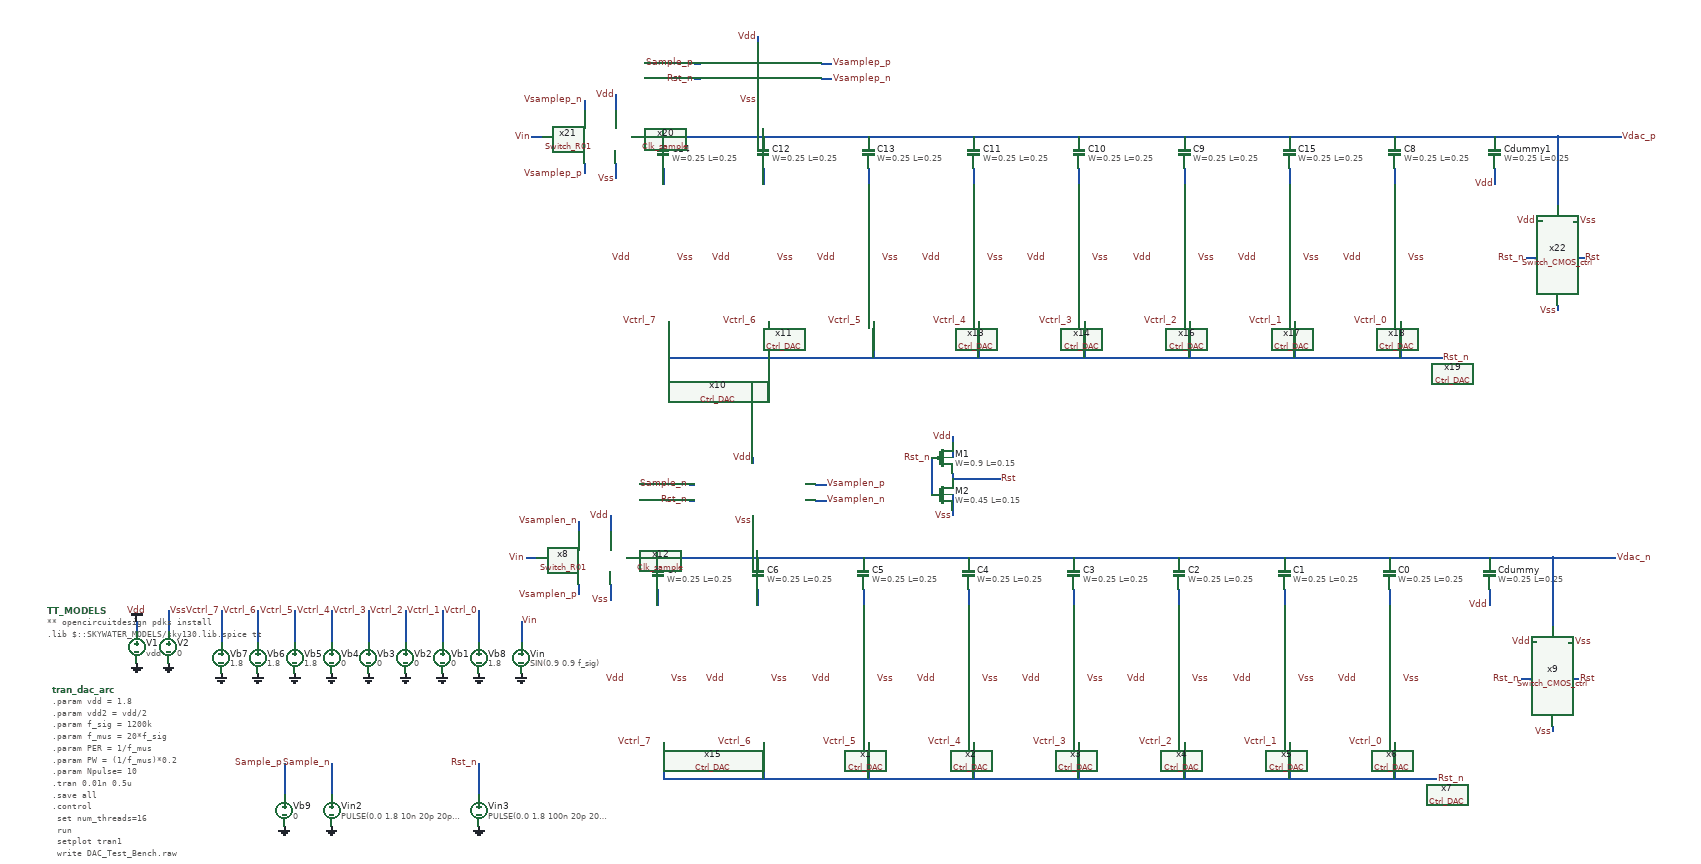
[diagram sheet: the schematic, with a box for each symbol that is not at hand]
v {xschem version=3.4.6RC file_version=1.2
}
G {}
K {}
V {}
S {}
E {}
B 2 10 -920 810 -520 {flags=graph


ypos1=0
ypos2=2
divy=5
subdivy=1
unity=1
x1=0

divx=5
subdivx=4
xlabmag=1.0
ylabmag=1.0


dataset=-1
unitx=1
logx=0
logy=0



linewidth_mult=2


hilight_wave=-1






node="Sample_n	
Vin
En_DAC
Vdac_p
Vdac_n
Rst"
x2=5e-07
y2=1.85
y1=-0.05
color="6 21 4 20 13 8"}
B 2 10 -1320 810 -920 {flags=graph


ypos1=0
ypos2=2
divy=5
subdivy=1
unity=1
x1=0

divx=5
subdivx=4
xlabmag=1.0
ylabmag=1.0


dataset=-1
unitx=1
logx=0
logy=0



linewidth_mult=2


hilight_wave=-1






node="Vdac_p
Vdac_n
Rst"
x2=5e-07
y2=1.85
y1=-0.05
color="6 21 4"}
N 160 -440 160 -420 {
lab=Vdd}
N 220 -460 220 -420 {
lab=Vss}
N 390 -460 390 -400 {
lab=Vctrl_6}
N 320 -460 320 -400 {
lab=Vctrl_7}
N 530 -460 530 -400 {
lab=Vctrl_4}
N 460 -460 460 -400 {
lab=Vctrl_5}
N 670 -460 670 -400 {
lab=Vctrl_2}
N 600 -460 600 -400 {
lab=Vctrl_3}
N 810 -460 810 -400 {
lab=Vctrl_0}
N 740 -460 740 -400 {
lab=Vctrl_1}
N 440 -170 440 -110 {
lab=Sample_p}
N 1150 -500 1150 -470 {lab=#net1}
N 1340 -500 1340 -470 {lab=#net2}
N 1540 -500 1540 -470 {lab=#net3}
N 1740 -500 1740 -470 {lab=#net4}
N 1940 -500 1940 -470 {lab=#net5}
N 2140 -500 2140 -470 {lab=#net6}
N 2340 -500 2340 -470 {lab=#net7}
N 2540 -500 2540 -470 {lab=#net8}
N 2730 -500 2730 -470 {lab=Vdd}
N 1150 -560 2730 -560 {lab=Vdac_n}
N 1210 -700 1220 -700 {lab=Sample_n}
N 1210 -670 1220 -670 {lab=Rst_n}
N 1330 -640 1330 -630 {lab=Vss}
N 1330 -750 1330 -740 {lab=Vdd}
N 1450 -700 1470 -700 {lab=Vsamplen_p}
N 1450 -670 1470 -670 {lab=Vsamplen_n}
N 2730 -560 2850 -560 {lab=Vdac_n}
N 1000 -630 1000 -610 {lab=Vsamplen_n}
N 1000 -510 1000 -490 {lab=Vsamplen_p}
N 1060 -510 1060 -480 {lab=Vss}
N 1060 -640 1060 -610 {lab=Vdd}
N 900 -560 920 -560 {lab=Vin}
N 1160 -140 2630 -140 {lab=Rst_n}
N 1160 -210 1160 -140 {lab=Rst_n}
N 1350 -210 1350 -140 {lab=Rst_n}
N 2550 -210 2550 -140 {lab=Rst_n}
N 2350 -210 2350 -140 {lab=Rst_n}
N 2150 -210 2150 -140 {lab=Rst_n}
N 1950 -210 1950 -140 {lab=Rst_n}
N 1750 -210 1750 -140 {lab=Rst_n}
N 1550 -210 1550 -140 {lab=Rst_n}
N 1710 -720 1710 -710 {lab=Rst}
N 1710 -790 1710 -750 {lab=Vdd}
N 1710 -680 1710 -640 {lab=Vss}
N 1670 -750 1670 -680 {lab=Rst_n}
N 890 -440 890 -400 {
lab=Vin}
N 810 -170 810 -110 {
lab=Rst_n}
N 2810 -400 2820 -400 {lab=Vdd}
N 2880 -400 2890 -400 {lab=Vss}
N 2850 -240 2850 -230 {lab=Vss}
N 2790 -330 2810 -330 {lab=Rst_n}
N 2890 -330 2900 -330 {lab=Rst}
N 2850 -560 2850 -430 {lab=Vdac_n}
N 2850 -560 2970 -560 {lab=Vdac_n}
N 1090 -560 1150 -560 {lab=Vdac_n}
N 1710 -710 1800 -710 {lab=Rst}
N 1160 -1300 1160 -1270 {lab=#net9}
N 1350 -1300 1350 -1270 {lab=#net10}
N 1550 -1300 1550 -1270 {lab=#net11}
N 1750 -1300 1750 -1270 {lab=#net12}
N 1950 -1300 1950 -1270 {lab=#net13}
N 2150 -1300 2150 -1270 {lab=#net14}
N 2350 -1300 2350 -1270 {lab=#net15}
N 2550 -1300 2550 -1270 {lab=#net16}
N 2740 -1300 2740 -1270 {lab=Vdd}
N 1160 -1360 2740 -1360 {lab=Vdac_p}
N 1220 -1500 1230 -1500 {lab=Sample_p}
N 1220 -1470 1230 -1470 {lab=Rst_n}
N 1340 -1440 1340 -1430 {lab=Vss}
N 1340 -1550 1340 -1540 {lab=Vdd}
N 1460 -1500 1480 -1500 {lab=Vsamplep_p}
N 1460 -1470 1480 -1470 {lab=Vsamplep_n}
N 2740 -1360 2860 -1360 {lab=Vdac_p}
N 1010 -1430 1010 -1410 {lab=Vsamplep_n}
N 1010 -1310 1010 -1290 {lab=Vsamplep_p}
N 1070 -1310 1070 -1280 {lab=Vss}
N 1070 -1440 1070 -1410 {lab=Vdd}
N 910 -1360 930 -1360 {lab=Vin}
N 1170 -940 2640 -940 {lab=Rst_n}
N 1170 -1010 1170 -940 {lab=Rst_n}
N 1360 -1010 1360 -940 {lab=Rst_n}
N 2560 -1010 2560 -940 {lab=Rst_n}
N 2360 -1010 2360 -940 {lab=Rst_n}
N 2160 -1010 2160 -940 {lab=Rst_n}
N 1960 -1010 1960 -940 {lab=Rst_n}
N 1760 -1010 1760 -940 {lab=Rst_n}
N 1560 -1010 1560 -940 {lab=Rst_n}
N 2820 -1200 2830 -1200 {lab=Vdd}
N 2890 -1200 2900 -1200 {lab=Vss}
N 2860 -1040 2860 -1030 {lab=Vss}
N 2800 -1130 2820 -1130 {lab=Rst_n}
N 2900 -1130 2910 -1130 {lab=Rst}
N 2860 -1360 2860 -1230 {lab=Vdac_p}
N 2860 -1360 2980 -1360 {lab=Vdac_p}
N 1100 -1360 1160 -1360 {lab=Vdac_p}
N 530 -170 530 -110 {
lab=Sample_n}
C {devices/code.sym} -10 -460 0 0 {name=TT_MODELS
only_toplevel=true
format="tcleval( @value )"
value="
** opencircuitdesign pdks install
.lib $::SKYWATER_MODELS/sky130.lib.spice tt

"
spice_ignore=false}
C {devices/code_shown.sym} 0 -310 0 0 {name=tran_dac_arc only_toplevel=false value="
.param vdd = 1.8
.param vdd2 = vdd/2
.param f_sig = 1200k
.param f_mus = 20*f_sig
.param PER   = 1/f_mus
.param PW    = (1/f_mus)*0.2
.param Npulse= 10
.tran 0.01n 0.5u
.save all
.control
	set num_threads=16
	run
	setplot tran1
	write DAC_Test_Bench.raw
.endc
"}
C {devices/launcher.sym} 380 -260 0 0 {name=h1
descr="load waves" 
tclcommand="xschem raw_read $netlist_dir/DAC_Test_Bench.raw tran"
}
C {devices/vsource.sym} 160 -390 0 0 {name=V1 value=vdd savecurrent=false}
C {devices/gnd.sym} 160 -360 0 0 {name=l1 lab=GND}
C {devices/vdd.sym} 160 -440 0 0 {name=l7 lab=Vdd}
C {devices/gnd.sym} 220 -360 0 0 {name=l5 lab=GND}
C {devices/lab_wire.sym} 220 -460 0 1 {name=p11 sig_type=std_logic lab=Vss}
C {devices/vsource.sym} 220 -390 0 0 {name=V2 value=0 savecurrent=false}
C {devices/lab_wire.sym} 320 -460 0 0 {name=p99 sig_type=std_logic lab=Vctrl_7}
C {devices/gnd.sym} 390 -340 0 0 {name=l9 lab=GND}
C {devices/gnd.sym} 320 -340 0 0 {name=l10 lab=GND}
C {devices/lab_wire.sym} 390 -460 0 0 {name=p100 sig_type=std_logic lab=Vctrl_6}
C {devices/lab_wire.sym} 460 -460 0 0 {name=p101 sig_type=std_logic lab=Vctrl_5}
C {devices/gnd.sym} 530 -340 0 0 {name=l11 lab=GND}
C {devices/gnd.sym} 460 -340 0 0 {name=l12 lab=GND}
C {devices/lab_wire.sym} 530 -460 0 0 {name=p102 sig_type=std_logic lab=Vctrl_4}
C {devices/lab_wire.sym} 600 -460 0 0 {name=p103 sig_type=std_logic lab=Vctrl_3}
C {devices/gnd.sym} 670 -340 0 0 {name=l13 lab=GND}
C {devices/gnd.sym} 600 -340 0 0 {name=l14 lab=GND}
C {devices/lab_wire.sym} 670 -460 0 0 {name=p104 sig_type=std_logic lab=Vctrl_2}
C {devices/lab_wire.sym} 740 -460 0 0 {name=p105 sig_type=std_logic lab=Vctrl_1}
C {devices/gnd.sym} 810 -340 0 0 {name=l15 lab=GND}
C {devices/gnd.sym} 740 -340 0 0 {name=l16 lab=GND}
C {devices/lab_wire.sym} 810 -460 0 0 {name=p106 sig_type=std_logic lab=Vctrl_0}
C {devices/vsource.sym} 320 -370 0 0 {name=Vb7 value=1.8 savecurrent=false}
C {devices/vsource.sym} 740 -370 0 0 {name=Vb1 value=0 savecurrent=false}
C {devices/vsource.sym} 670 -370 0 0 {name=Vb2 value=0 savecurrent=false}
C {devices/vsource.sym} 600 -370 0 0 {name=Vb3 value=0 savecurrent=false}
C {devices/vsource.sym} 530 -370 0 0 {name=Vb4 value=0 savecurrent=false}
C {devices/vsource.sym} 460 -370 0 0 {name=Vb5 value=1.8 savecurrent=false}
C {devices/vsource.sym} 390 -370 0 0 {name=Vb6 value=1.8 savecurrent=false}
C {devices/vsource.sym} 810 -370 0 0 {name=Vb8 value=1.8 savecurrent=false}
C {devices/gnd.sym} 440 -50 0 0 {name=l4 lab=GND}
C {devices/vsource.sym} 530 -80 0 0 {name=Vin2 value="PULSE(0.0 1.8 10n 20p 20p 10n 60n)" }
C {devices/lab_wire.sym} 440 -170 0 0 {name=p4 sig_type=std_logic lab=Sample_p}
C {devices/lab_wire.sym} 2970 -560 2 0 {name=p2 sig_type=std_logic lab=Vdac_n}
C {sky130_fd_pr/cap_mim_m3_1.sym} 2540 -530 0 0 {name=C0 model=cap_mim_m3_1 W=0.25 L=0.25 MF=1 spiceprefix=X}
C {sky130_fd_pr/cap_mim_m3_1.sym} 2140 -530 0 0 {name=C2 model=cap_mim_m3_1 W=0.25 L=0.25 MF=4 spiceprefix=X}
C {sky130_fd_pr/cap_mim_m3_1.sym} 1940 -530 0 0 {name=C3 model=cap_mim_m3_1 W=0.25 L=0.25 MF=8 spiceprefix=X}
C {sky130_fd_pr/cap_mim_m3_1.sym} 1740 -530 0 0 {name=C4 model=cap_mim_m3_1 W=0.25 L=0.25 MF=16 spiceprefix=X}
C {sky130_fd_pr/cap_mim_m3_1.sym} 1340 -530 0 0 {name=C6 model=cap_mim_m3_1 W=0.25 L=0.25 MF=64 spiceprefix=X}
C {sky130_fd_pr/cap_mim_m3_1.sym} 1540 -530 0 0 {name=C5 model=cap_mim_m3_1 W=0.25 L=0.25 MF=32 spiceprefix=X}
C {sky130_fd_pr/cap_mim_m3_1.sym} 1150 -530 0 0 {name=C7 model=cap_mim_m3_1 W=0.25 L=0.25 MF=128 spiceprefix=X}
C {sky130_fd_pr/cap_mim_m3_1.sym} 2340 -530 0 0 {name=C1 model=cap_mim_m3_1 W=0.25 L=0.25 MF=2 spiceprefix=X}
C {sky130_fd_pr/cap_mim_m3_1.sym} 2730 -530 0 0 {name=Cdummy model=cap_mim_m3_1 W=0.25 L=0.25 MF=1 spiceprefix=X}
C {devices/lab_pin.sym} 2730 -470 1 1 {name=p3 sig_type=std_logic lab=Vdd}
C {/home/cic/Documents/Sky_130nm/Capacitive_DAC/Ctrl_DAC.sym} 1260 -110 3 0 {name=x15}
C {devices/lab_wire.sym} 1090 -330 3 0 {name=p42 sig_type=std_logic lab=Vdd}
C {devices/lab_wire.sym} 1210 -330 1 1 {name=p44 sig_type=std_logic lab=Vss}
C {devices/lab_wire.sym} 1140 -210 3 0 {name=p46 sig_type=std_logic lab=Vctrl_7}
C {/home/cic/Documents/Sky_130nm/Capacitive_DAC/Ctrl_DAC.sym} 1450 -110 3 0 {name=x1}
C {devices/lab_wire.sym} 1280 -330 3 0 {name=p7 sig_type=std_logic lab=Vdd}
C {devices/lab_wire.sym} 1400 -330 1 1 {name=p8 sig_type=std_logic lab=Vss}
C {devices/lab_wire.sym} 1330 -210 3 0 {name=p10 sig_type=std_logic lab=Vctrl_6}
C {/home/cic/Documents/Sky_130nm/Capacitive_DAC/Ctrl_DAC.sym} 1650 -110 3 0 {name=x2}
C {devices/lab_wire.sym} 1480 -330 3 0 {name=p12 sig_type=std_logic lab=Vdd}
C {devices/lab_wire.sym} 1600 -330 1 1 {name=p13 sig_type=std_logic lab=Vss}
C {/home/cic/Documents/Sky_130nm/Capacitive_DAC/Ctrl_DAC.sym} 1850 -110 3 0 {name=x3}
C {devices/lab_wire.sym} 1680 -330 3 0 {name=p14 sig_type=std_logic lab=Vdd}
C {devices/lab_wire.sym} 1800 -330 1 1 {name=p15 sig_type=std_logic lab=Vss}
C {/home/cic/Documents/Sky_130nm/Capacitive_DAC/Ctrl_DAC.sym} 2050 -110 3 0 {name=x4}
C {devices/lab_wire.sym} 1880 -330 3 0 {name=p17 sig_type=std_logic lab=Vdd}
C {devices/lab_wire.sym} 2000 -330 1 1 {name=p18 sig_type=std_logic lab=Vss}
C {/home/cic/Documents/Sky_130nm/Capacitive_DAC/Ctrl_DAC.sym} 2250 -110 3 0 {name=x5}
C {devices/lab_wire.sym} 2080 -330 3 0 {name=p20 sig_type=std_logic lab=Vdd}
C {devices/lab_wire.sym} 2200 -330 1 1 {name=p21 sig_type=std_logic lab=Vss}
C {/home/cic/Documents/Sky_130nm/Capacitive_DAC/Ctrl_DAC.sym} 2450 -110 3 0 {name=x6}
C {devices/lab_wire.sym} 2280 -330 3 0 {name=p23 sig_type=std_logic lab=Vdd}
C {devices/lab_wire.sym} 2400 -330 1 1 {name=p24 sig_type=std_logic lab=Vss}
C {/home/cic/Documents/Sky_130nm/Capacitive_DAC/Ctrl_DAC.sym} 2650 -110 3 0 {name=x7}
C {devices/lab_wire.sym} 2480 -330 3 0 {name=p26 sig_type=std_logic lab=Vdd}
C {devices/lab_wire.sym} 2600 -330 1 1 {name=p27 sig_type=std_logic lab=Vss}
C {devices/lab_wire.sym} 1530 -210 3 0 {name=p29 sig_type=std_logic lab=Vctrl_5}
C {devices/lab_wire.sym} 1730 -210 3 0 {name=p30 sig_type=std_logic lab=Vctrl_4}
C {devices/lab_wire.sym} 1930 -210 3 0 {name=p31 sig_type=std_logic lab=Vctrl_3}
C {devices/lab_wire.sym} 2130 -210 3 0 {name=p32 sig_type=std_logic lab=Vctrl_2}
C {devices/lab_wire.sym} 2330 -210 3 0 {name=p33 sig_type=std_logic lab=Vctrl_1}
C {devices/lab_wire.sym} 2530 -210 3 0 {name=p34 sig_type=std_logic lab=Vctrl_0}
C {devices/lab_pin.sym} 1470 -700 0 1 {name=p139 sig_type=std_logic lab=Vsamplen_p}
C {devices/lab_pin.sym} 1470 -670 0 1 {name=p140 sig_type=std_logic lab=Vsamplen_n}
C {/home/cic/Documents/Sky_130nm/Clock/Clk_sample.sym} 1150 -550 0 0 {name=x12}
C {devices/lab_pin.sym} 1330 -630 3 0 {name=p141 sig_type=std_logic lab=Vss}
C {devices/lab_pin.sym} 1330 -750 3 1 {name=p142 sig_type=std_logic lab=Vdd}
C {devices/lab_pin.sym} 1210 -700 0 0 {name=p143 sig_type=std_logic lab=Sample_n}
C {/home/cic/Documents/Sky_130nm/Switches/Switch_R01.sym} 890 -470 0 0 {name=x8}
C {devices/lab_pin.sym} 1000 -630 3 1 {name=p35 sig_type=std_logic lab=Vsamplen_n}
C {devices/lab_pin.sym} 1000 -490 1 1 {name=p36 sig_type=std_logic lab=Vsamplen_p}
C {devices/lab_pin.sym} 1060 -640 3 1 {name=p37 sig_type=std_logic lab=Vdd}
C {devices/lab_pin.sym} 1060 -480 3 0 {name=p38 sig_type=std_logic lab=Vss}
C {devices/lab_wire.sym} 900 -560 0 0 {name=p39 sig_type=std_logic lab=Vin}
C {sky130_fd_pr/pfet_01v8.sym} 1690 -750 0 0 {name=M1
L=0.15
W=0.9
nf=1
mult=1
ad="'int((nf+1)/2) * W/nf * 0.29'" 
pd="'2*int((nf+1)/2) * (W/nf + 0.29)'"
as="'int((nf+2)/2) * W/nf * 0.29'" 
ps="'2*int((nf+2)/2) * (W/nf + 0.29)'"
nrd="'0.29 / W'" nrs="'0.29 / W'"
sa=0 sb=0 sd=0
model=pfet_01v8
spiceprefix=X
}
C {sky130_fd_pr/nfet_01v8.sym} 1690 -680 0 0 {name=M2
L=0.15
W=0.45
nf=1 
mult=1
ad="'int((nf+1)/2) * W/nf * 0.29'" 
pd="'2*int((nf+1)/2) * (W/nf + 0.29)'"
as="'int((nf+2)/2) * W/nf * 0.29'" 
ps="'2*int((nf+2)/2) * (W/nf + 0.29)'"
nrd="'0.29 / W'" nrs="'0.29 / W'"
sa=0 sb=0 sd=0
model=nfet_01v8
spiceprefix=X
}
C {devices/lab_pin.sym} 1710 -640 1 1 {name=p6 sig_type=std_logic lab=Vss}
C {devices/lab_pin.sym} 1710 -790 3 1 {name=p9 sig_type=std_logic lab=Vdd}
C {devices/gnd.sym} 890 -340 0 0 {name=l3 lab=GND}
C {devices/vsource.sym} 890 -370 0 0 {name=Vin value="SIN(0.9 0.9 f_sig)" }
C {devices/lab_wire.sym} 890 -440 0 1 {name=p19 sig_type=std_logic lab=Vin}
C {devices/gnd.sym} 810 -50 0 0 {name=l6 lab=GND}
C {devices/vsource.sym} 810 -80 0 0 {name=Vin3 value="PULSE(0.0 1.8 100n 20p 20p 1000n 1000n)" }
C {devices/lab_pin.sym} 810 -170 2 1 {name=p25 sig_type=std_logic lab=Rst_n}
C {/home/cic/Documents/Sky_130nm/Switches/Switch_CMOS_ctrl.sym} 2920 -210 3 0 {name=x9}
C {devices/lab_pin.sym} 2810 -400 2 1 {name=p49 sig_type=std_logic lab=Vdd}
C {devices/lab_pin.sym} 2890 -400 0 1 {name=p50 sig_type=std_logic lab=Vss}
C {devices/lab_pin.sym} 2850 -230 1 1 {name=p51 sig_type=std_logic lab=Vss}
C {devices/vsource.sym} 440 -80 0 0 {name=Vb9 value=0 savecurrent=false}
C {devices/lab_wire.sym} 2980 -1360 2 0 {name=p28 sig_type=std_logic lab=Vdac_p}
C {sky130_fd_pr/cap_mim_m3_1.sym} 2550 -1330 0 0 {name=C8 model=cap_mim_m3_1 W=0.25 L=0.25 MF=1 spiceprefix=X}
C {sky130_fd_pr/cap_mim_m3_1.sym} 2150 -1330 0 0 {name=C9 model=cap_mim_m3_1 W=0.25 L=0.25 MF=4 spiceprefix=X}
C {sky130_fd_pr/cap_mim_m3_1.sym} 1950 -1330 0 0 {name=C10 model=cap_mim_m3_1 W=0.25 L=0.25 MF=8 spiceprefix=X}
C {sky130_fd_pr/cap_mim_m3_1.sym} 1750 -1330 0 0 {name=C11 model=cap_mim_m3_1 W=0.25 L=0.25 MF=16 spiceprefix=X}
C {sky130_fd_pr/cap_mim_m3_1.sym} 1350 -1330 0 0 {name=C12 model=cap_mim_m3_1 W=0.25 L=0.25 MF=64 spiceprefix=X}
C {sky130_fd_pr/cap_mim_m3_1.sym} 1550 -1330 0 0 {name=C13 model=cap_mim_m3_1 W=0.25 L=0.25 MF=32 spiceprefix=X}
C {sky130_fd_pr/cap_mim_m3_1.sym} 1160 -1330 0 0 {name=C14 model=cap_mim_m3_1 W=0.25 L=0.25 MF=128 spiceprefix=X}
C {sky130_fd_pr/cap_mim_m3_1.sym} 2350 -1330 0 0 {name=C15 model=cap_mim_m3_1 W=0.25 L=0.25 MF=2 spiceprefix=X}
C {sky130_fd_pr/cap_mim_m3_1.sym} 2740 -1330 0 0 {name=Cdummy1 model=cap_mim_m3_1 W=0.25 L=0.25 MF=1 spiceprefix=X}
C {devices/lab_pin.sym} 2740 -1270 1 1 {name=p40 sig_type=std_logic lab=Vdd}
C {/home/cic/Documents/Sky_130nm/Capacitive_DAC/Ctrl_DAC.sym} 1270 -910 3 0 {name=x10}
C {devices/lab_wire.sym} 1100 -1130 3 0 {name=p41 sig_type=std_logic lab=Vdd}
C {devices/lab_wire.sym} 1220 -1130 1 1 {name=p43 sig_type=std_logic lab=Vss}
C {devices/lab_wire.sym} 1150 -1010 3 0 {name=p45 sig_type=std_logic lab=Vctrl_7}
C {/home/cic/Documents/Sky_130nm/Capacitive_DAC/Ctrl_DAC.sym} 1460 -910 3 0 {name=x11}
C {devices/lab_wire.sym} 1290 -1130 3 0 {name=p47 sig_type=std_logic lab=Vdd}
C {devices/lab_wire.sym} 1410 -1130 1 1 {name=p48 sig_type=std_logic lab=Vss}
C {devices/lab_wire.sym} 1340 -1010 3 0 {name=p52 sig_type=std_logic lab=Vctrl_6}
C {/home/cic/Documents/Sky_130nm/Capacitive_DAC/Ctrl_DAC.sym} 1660 -910 3 0 {name=x13}
C {devices/lab_wire.sym} 1490 -1130 3 0 {name=p53 sig_type=std_logic lab=Vdd}
C {devices/lab_wire.sym} 1610 -1130 1 1 {name=p55 sig_type=std_logic lab=Vss}
C {/home/cic/Documents/Sky_130nm/Capacitive_DAC/Ctrl_DAC.sym} 1860 -910 3 0 {name=x14}
C {devices/lab_wire.sym} 1690 -1130 3 0 {name=p56 sig_type=std_logic lab=Vdd}
C {devices/lab_wire.sym} 1810 -1130 1 1 {name=p63 sig_type=std_logic lab=Vss}
C {/home/cic/Documents/Sky_130nm/Capacitive_DAC/Ctrl_DAC.sym} 2060 -910 3 0 {name=x16}
C {devices/lab_wire.sym} 1890 -1130 3 0 {name=p64 sig_type=std_logic lab=Vdd}
C {devices/lab_wire.sym} 2010 -1130 1 1 {name=p65 sig_type=std_logic lab=Vss}
C {/home/cic/Documents/Sky_130nm/Capacitive_DAC/Ctrl_DAC.sym} 2260 -910 3 0 {name=x17}
C {devices/lab_wire.sym} 2090 -1130 3 0 {name=p66 sig_type=std_logic lab=Vdd}
C {devices/lab_wire.sym} 2210 -1130 1 1 {name=p67 sig_type=std_logic lab=Vss}
C {/home/cic/Documents/Sky_130nm/Capacitive_DAC/Ctrl_DAC.sym} 2460 -910 3 0 {name=x18}
C {devices/lab_wire.sym} 2290 -1130 3 0 {name=p68 sig_type=std_logic lab=Vdd}
C {devices/lab_wire.sym} 2410 -1130 1 1 {name=p69 sig_type=std_logic lab=Vss}
C {/home/cic/Documents/Sky_130nm/Capacitive_DAC/Ctrl_DAC.sym} 2660 -910 3 0 {name=x19}
C {devices/lab_wire.sym} 2490 -1130 3 0 {name=p70 sig_type=std_logic lab=Vdd}
C {devices/lab_wire.sym} 2610 -1130 1 1 {name=p71 sig_type=std_logic lab=Vss}
C {devices/lab_wire.sym} 1540 -1010 3 0 {name=p72 sig_type=std_logic lab=Vctrl_5}
C {devices/lab_wire.sym} 1740 -1010 3 0 {name=p73 sig_type=std_logic lab=Vctrl_4}
C {devices/lab_wire.sym} 1940 -1010 3 0 {name=p74 sig_type=std_logic lab=Vctrl_3}
C {devices/lab_wire.sym} 2140 -1010 3 0 {name=p75 sig_type=std_logic lab=Vctrl_2}
C {devices/lab_wire.sym} 2340 -1010 3 0 {name=p76 sig_type=std_logic lab=Vctrl_1}
C {devices/lab_wire.sym} 2540 -1010 3 0 {name=p77 sig_type=std_logic lab=Vctrl_0}
C {devices/lab_pin.sym} 1480 -1500 0 1 {name=p78 sig_type=std_logic lab=Vsamplep_p}
C {devices/lab_pin.sym} 1480 -1470 0 1 {name=p79 sig_type=std_logic lab=Vsamplep_n}
C {/home/cic/Documents/Sky_130nm/Clock/Clk_sample.sym} 1160 -1350 0 0 {name=x20}
C {devices/lab_pin.sym} 1340 -1430 3 0 {name=p80 sig_type=std_logic lab=Vss}
C {devices/lab_pin.sym} 1340 -1550 3 1 {name=p81 sig_type=std_logic lab=Vdd}
C {devices/lab_pin.sym} 1220 -1500 0 0 {name=p82 sig_type=std_logic lab=Sample_p}
C {/home/cic/Documents/Sky_130nm/Switches/Switch_R01.sym} 900 -1270 0 0 {name=x21}
C {devices/lab_pin.sym} 1010 -1430 3 1 {name=p84 sig_type=std_logic lab=Vsamplep_n}
C {devices/lab_pin.sym} 1010 -1290 1 1 {name=p85 sig_type=std_logic lab=Vsamplep_p}
C {devices/lab_pin.sym} 1070 -1440 3 1 {name=p86 sig_type=std_logic lab=Vdd}
C {devices/lab_pin.sym} 1070 -1280 3 0 {name=p87 sig_type=std_logic lab=Vss}
C {devices/lab_wire.sym} 910 -1360 0 0 {name=p88 sig_type=std_logic lab=Vin}
C {/home/cic/Documents/Sky_130nm/Switches/Switch_CMOS_ctrl.sym} 2930 -1010 3 0 {name=x22}
C {devices/lab_pin.sym} 2820 -1200 2 1 {name=p95 sig_type=std_logic lab=Vdd}
C {devices/lab_pin.sym} 2900 -1200 0 1 {name=p96 sig_type=std_logic lab=Vss}
C {devices/lab_pin.sym} 2860 -1030 1 1 {name=p97 sig_type=std_logic lab=Vss}
C {devices/gnd.sym} 530 -50 0 0 {name=l17 lab=GND}
C {devices/lab_wire.sym} 530 -170 0 0 {name=p90 sig_type=std_logic lab=Sample_n}
C {devices/lab_pin.sym} 2630 -140 0 1 {name=p1 sig_type=std_logic lab=Rst_n}
C {devices/lab_pin.sym} 2790 -330 2 1 {name=p5 sig_type=std_logic lab=Rst_n}
C {devices/lab_pin.sym} 2900 -330 0 1 {name=p54 sig_type=std_logic lab=Rst}
C {devices/lab_pin.sym} 1800 -710 0 1 {name=p57 sig_type=std_logic lab=Rst}
C {devices/lab_pin.sym} 1210 -670 0 0 {name=p58 sig_type=std_logic lab=Rst_n}
C {devices/lab_pin.sym} 1670 -750 0 0 {name=p16 sig_type=std_logic lab=Rst_n}
C {devices/lab_pin.sym} 2800 -1130 0 0 {name=p22 sig_type=std_logic lab=Rst_n}
C {devices/lab_pin.sym} 2640 -940 2 0 {name=p59 sig_type=std_logic lab=Rst_n}
C {devices/lab_pin.sym} 2910 -1130 0 1 {name=p60 sig_type=std_logic lab=Rst}
C {devices/lab_pin.sym} 1220 -1470 0 0 {name=p61 sig_type=std_logic lab=Rst_n}
